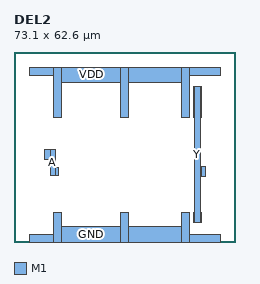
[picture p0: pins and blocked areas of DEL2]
MACRO DEL2
  CLASS CORE ;
  ORIGIN 0 0 ;
  SIZE 73.100 BY 62.600 ;
  SYMMETRY X Y ;
  SITE TR1um_site ;
  PIN VDD
    DIRECTION INOUT ;
    USE POWER ;
    PORT
      LAYER M1 ;
        RECT 5.000 55.000 13.100 57.600 ;
      LAYER M1 ;
        RECT 13.100 41.000 15.700 57.600 ;
      LAYER M1 ;
        RECT 15.700 52.600 35.100 57.600 ;
      LAYER M1 ;
        RECT 35.100 41.000 37.700 57.600 ;
      LAYER M1 ;
        RECT 37.700 52.600 55.100 57.600 ;
      LAYER M1 ;
        RECT 55.100 41.000 57.700 57.600 ;
      LAYER M1 ;
        RECT 57.700 55.000 68.100 57.600 ;
    END
  END VDD
  PIN Y
    DIRECTION OUTPUT ;
    USE SIGNAL ;
    PORT
      LAYER M1 ;
        RECT 59.100 6.400 59.500 9.800 ;
      LAYER M1 ;
        RECT 59.100 41.000 59.500 51.200 ;
      LAYER M1 ;
        RECT 59.500 6.400 61.300 51.200 ;
      LAYER M1 ;
        RECT 61.300 6.400 61.700 9.800 ;
      LAYER M1 ;
        RECT 61.300 21.600 61.700 25.000 ;
      LAYER M1 ;
        RECT 61.300 41.000 61.700 51.200 ;
      LAYER M1 ;
        RECT 61.700 21.600 63.000 25.000 ;
    END
  END Y
  PIN A
    DIRECTION INPUT ;
    USE SIGNAL ;
    PORT
      LAYER M1 ;
        RECT 10.100 27.100 11.900 30.500 ;
      LAYER M1 ;
        RECT 11.900 22.000 13.700 30.500 ;
      LAYER M1 ;
        RECT 13.700 22.000 14.500 24.600 ;
    END
  END A
  PIN GND
    DIRECTION INOUT ;
    USE GROUND ;
    PORT
      LAYER M1 ;
        RECT 5.000 0.000 13.100 2.600 ;
      LAYER M1 ;
        RECT 13.100 0.000 15.700 9.800 ;
      LAYER M1 ;
        RECT 15.700 0.000 35.100 5.000 ;
      LAYER M1 ;
        RECT 35.100 0.000 37.700 9.800 ;
      LAYER M1 ;
        RECT 37.700 0.000 55.100 5.000 ;
      LAYER M1 ;
        RECT 55.100 0.000 57.700 9.800 ;
      LAYER M1 ;
        RECT 57.700 0.000 68.100 2.600 ;
    END
  END GND
END DEL2
